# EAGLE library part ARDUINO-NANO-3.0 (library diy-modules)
Arduino Nano 3.0 and compatible devices More details available here: https://www.arduino.cc/en/Main/ArduinoBoardNano Click here to find device on ebay.com

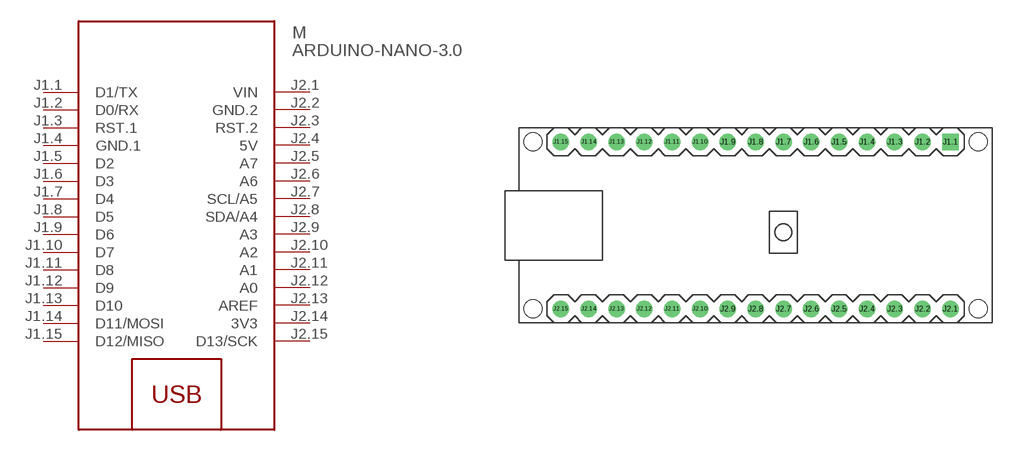
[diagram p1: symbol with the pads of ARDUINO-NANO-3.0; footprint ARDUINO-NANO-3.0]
Designator prefix M

## ARDUINO-NANO-3.0  [ARDUINO-NANO-3.0]
J1.1  D1/TX
J1.2  D0/RX
J1.3  RST.1
J1.4  GND.1  pwr
J1.5  D2
J1.6  D3
J1.7  D4
J1.8  D5
J1.9  D6
J1.10  D7
J1.11  D8
J1.12  D9
J1.13  D10
J1.14  D11/MOSI
J1.15  D12/MISO
J2.1  VIN  pwr
J2.2  GND.2  pwr
J2.3  RST.2
J2.4  5V  pwr
J2.5  A7
J2.6  A6
J2.7  SCL/A5
J2.8  SDA/A4
J2.9  A3
J2.10  A2
J2.11  A1
J2.12  A0
J2.13  AREF
J2.14  3V3  pwr
J2.15  D13/SCK

## Footprint ARDUINO-NANO-3.0 (pad centres in mm)
Arduino Nano 3.0
drill 1 square: J1.1 17.78,7.62
drill 1: J1.2 15.24,7.62; J1.3 12.7,7.62; J1.4 10.16,7.62; J1.5 7.62,7.62; J1.6 5.08,7.62; J1.7 2.54,7.62; J1.8 0,7.62; J1.9 -2.54,7.62; J1.10 -5.08,7.62; J1.11 -7.62,7.62; J1.12 -10.16,7.62; J1.13 -12.7,7.62; J1.14 -15.24,7.62; J1.15 -17.78,7.62; J2.1 17.78,-7.62; J2.2 15.24,-7.62; J2.3 12.7,-7.62; J2.4 10.16,-7.62; J2.5 7.62,-7.62; J2.6 5.08,-7.62; J2.7 2.54,-7.62; J2.8 0,-7.62; J2.9 -2.54,-7.62; J2.10 -5.08,-7.62; J2.11 -7.62,-7.62; J2.12 -10.16,-7.62; J2.13 -12.7,-7.62; J2.14 -15.24,-7.62; J2.15 -17.78,-7.62
hole 1.651 at -20.32,7.62
hole 1.651 at -20.32,-7.62
hole 1.651 at 20.32,-7.62
hole 1.651 at 20.32,7.62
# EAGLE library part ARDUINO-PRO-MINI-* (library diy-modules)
Arduino Pro Mini and compatible devices More details available here: https://www.arduino.cc/en/Main/ArduinoBoardProMini Click here to find device on ebay.com

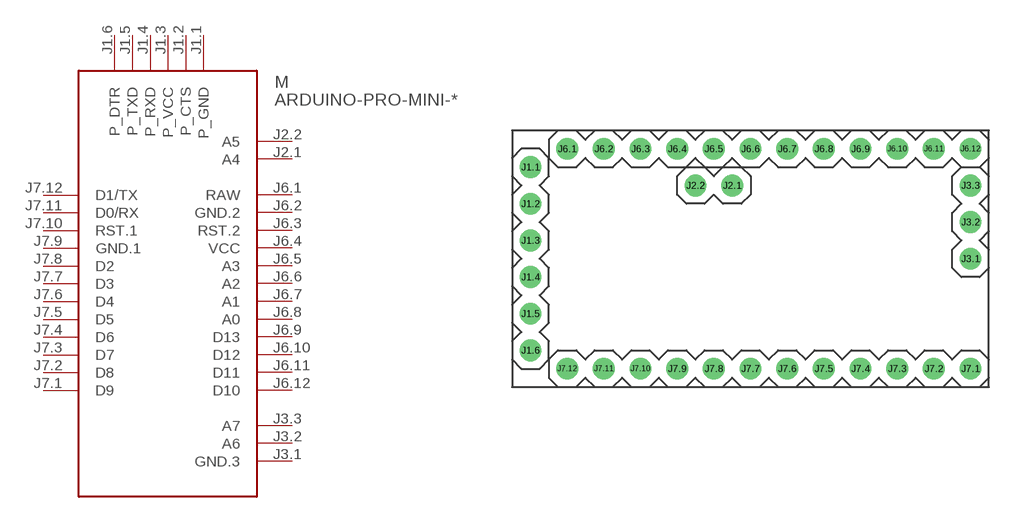
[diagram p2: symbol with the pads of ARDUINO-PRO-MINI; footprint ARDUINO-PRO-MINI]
Designator prefix M

## ARDUINO-PRO-MINI-3.3V, ARDUINO-PRO-MINI-5.0V  [ARDUINO-PRO-MINI]
J1.1  P_GND
J1.2  P_CTS
J1.3  P_VCC
J1.4  P_RXD
J1.5  P_TXD
J1.6  P_DTR
J2.1  A4
J2.2  A5
J3.1  GND.3
J3.2  A6
J3.3  A7
J6.1  RAW  pwr
J6.2  GND.2  pwr
J6.3  RST.2
J6.4  VCC  pwr
J6.5  A3
J6.6  A2
J6.7  A1
J6.8  A0
J6.9  D13
J6.10  D12
J6.11  D11
J6.12  D10
J7.1  D9
J7.2  D8
J7.3  D7
J7.4  D6
J7.5  D5
J7.6  D4
J7.7  D3
J7.8  D2
J7.9  GND.1  pwr
J7.10  RST.1
J7.11  D0/RX
J7.12  D1/TX

## Footprint ARDUINO-PRO-MINI (pad centres in mm)
Arduino Pro Mini
drill 1: J1.1 -15.24,6.35; J1.2 -15.24,3.81; J1.3 -15.24,1.27; J1.4 -15.24,-1.27; J1.5 -15.24,-3.81; J1.6 -15.24,-6.35; J2.1 -1.27,5.08; J2.2 -3.81,5.08; J3.1 15.24,0; J3.2 15.24,2.54; J3.3 15.24,5.08; J6.1 -12.7,7.62; J6.2 -10.16,7.62; J6.3 -7.62,7.62; J6.4 -5.08,7.62; J6.5 -2.54,7.62; J6.6 0,7.62; J6.7 2.54,7.62; J6.8 5.08,7.62; J6.9 7.62,7.62; J6.10 10.16,7.62; J6.11 12.7,7.62; J6.12 15.24,7.62; J7.1 15.24,-7.62; J7.2 12.7,-7.62; J7.3 10.16,-7.62; J7.4 7.62,-7.62; J7.5 5.08,-7.62; J7.6 2.54,-7.62; J7.7 0,-7.62; J7.8 -2.54,-7.62; J7.9 -5.08,-7.62; J7.10 -7.62,-7.62; J7.11 -10.16,-7.62; J7.12 -12.7,-7.62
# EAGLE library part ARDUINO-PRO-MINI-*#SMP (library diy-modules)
Arduino Pro Mini (and compatible devices) with 2 connectors only More details available here: https://www.arduino.cc/en/Main/ArduinoBoardProMini Click here to find device on ebay.com

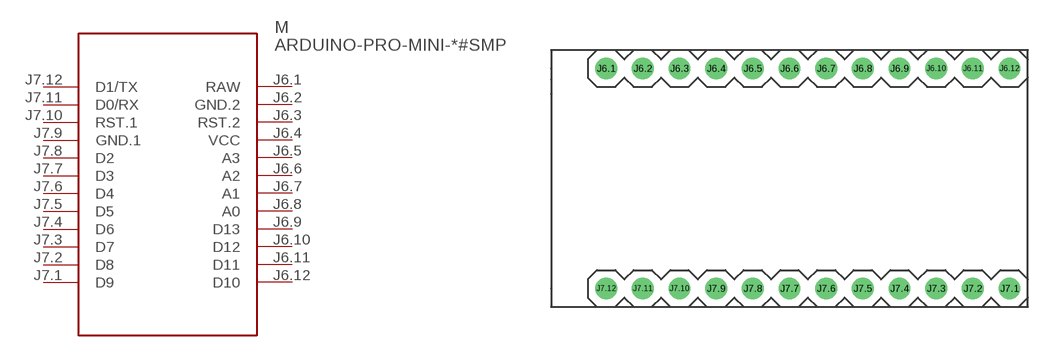
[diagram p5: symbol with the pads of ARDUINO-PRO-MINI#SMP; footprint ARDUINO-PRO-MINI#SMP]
Designator prefix M

## ARDUINO-PRO-MINI-3.3V#SMP, ARDUINO-PRO-MINI-5.0V#SMP  [ARDUINO-PRO-MINI#SMP]
J6.1  RAW  pwr
J6.2  GND.2  pwr
J6.3  RST.2
J6.4  VCC  pwr
J6.5  A3
J6.6  A2
J6.7  A1
J6.8  A0
J6.9  D13
J6.10  D12
J6.11  D11
J6.12  D10
J7.1  D9
J7.2  D8
J7.3  D7
J7.4  D6
J7.5  D5
J7.6  D4
J7.7  D3
J7.8  D2
J7.9  GND.1  pwr
J7.10  RST.1
J7.11  D0/RX
J7.12  D1/TX

## Footprint ARDUINO-PRO-MINI#SMP (pad centres in mm)
Arduino Pro Mini Footprint with 2 connectors only
drill 1: J6.1 -12.7,7.62; J6.2 -10.16,7.62; J6.3 -7.62,7.62; J6.4 -5.08,7.62; J6.5 -2.54,7.62; J6.6 0,7.62; J6.7 2.54,7.62; J6.8 5.08,7.62; J6.9 7.62,7.62; J6.10 10.16,7.62; J6.11 12.7,7.62; J6.12 15.24,7.62; J7.1 15.24,-7.62; J7.2 12.7,-7.62; J7.3 10.16,-7.62; J7.4 7.62,-7.62; J7.5 5.08,-7.62; J7.6 2.54,-7.62; J7.7 0,-7.62; J7.8 -2.54,-7.62; J7.9 -5.08,-7.62; J7.10 -7.62,-7.62; J7.11 -10.16,-7.62; J7.12 -12.7,-7.62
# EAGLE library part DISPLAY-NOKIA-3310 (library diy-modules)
84x48 Dot Matrix LCD Module based on Nokia 3310 display More details available here: https://arduinoandsoftware.wordpress.com/2012/12/30/nokia-33105110-3-3v-display-with-5v-arduino/

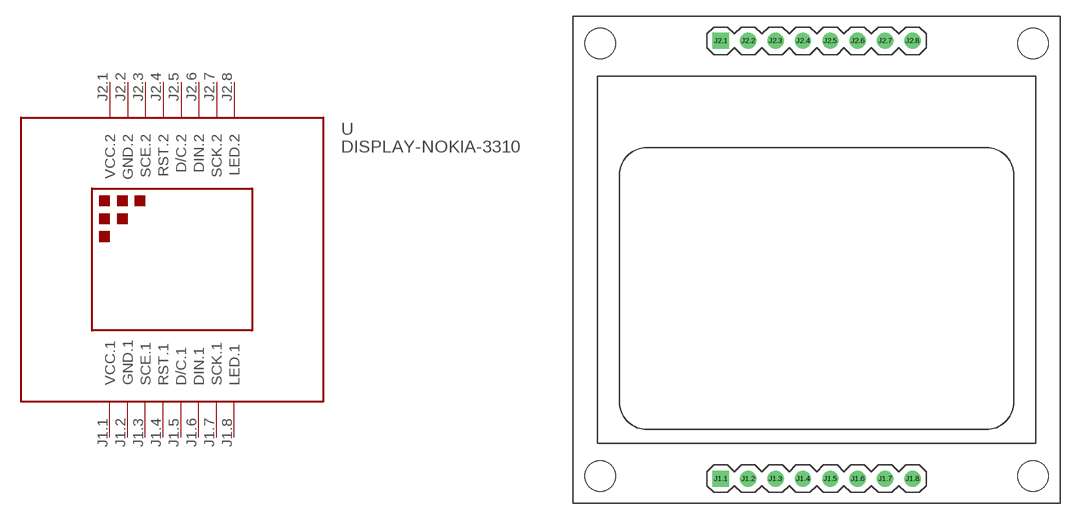
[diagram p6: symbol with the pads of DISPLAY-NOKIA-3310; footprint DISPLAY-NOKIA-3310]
Designator prefix -

## DISPLAY-NOKIA-3310  [DISPLAY-NOKIA-3310]
J1.1  VCC.1  pwr
J1.2  GND.1  pwr
J1.3  SCE.1
J1.4  RST.1
J1.5  D/C.1
J1.6  DIN.1
J1.7  SCK.1
J1.8  LED.1  in
J2.1  VCC.2  pwr
J2.2  GND.2  pwr
J2.3  SCE.2
J2.4  RST.2
J2.5  D/C.2
J2.6  DIN.2
J2.7  SCK.2
J2.8  LED.2  in

## Footprint DISPLAY-NOKIA-3310 (pad centres in mm)
84x48 Dot Matrix LCD Module based on Nokia 3310 display
drill 1 square: J1.1 -8.89,-20.32; J2.1 -8.89,20.32
drill 1: J1.2 -6.35,-20.32; J1.3 -3.81,-20.32; J1.4 -1.27,-20.32; J1.5 1.27,-20.32; J1.6 3.81,-20.32; J1.7 6.35,-20.32; J1.8 8.89,-20.32; J2.2 -6.35,20.32; J2.3 -3.81,20.32; J2.4 -1.27,20.32; J2.5 1.27,20.32; J2.6 3.81,20.32; J2.7 6.35,20.32; J2.8 8.89,20.32
hole 2.8 at -20.066,-20.066
hole 2.8 at 20.066,-20.066
hole 2.8 at 20.066,20.066
hole 2.8 at -20.066,20.066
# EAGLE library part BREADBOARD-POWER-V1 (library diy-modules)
Breadboard Power Adapter with onboard 3.3V and 5V regulators

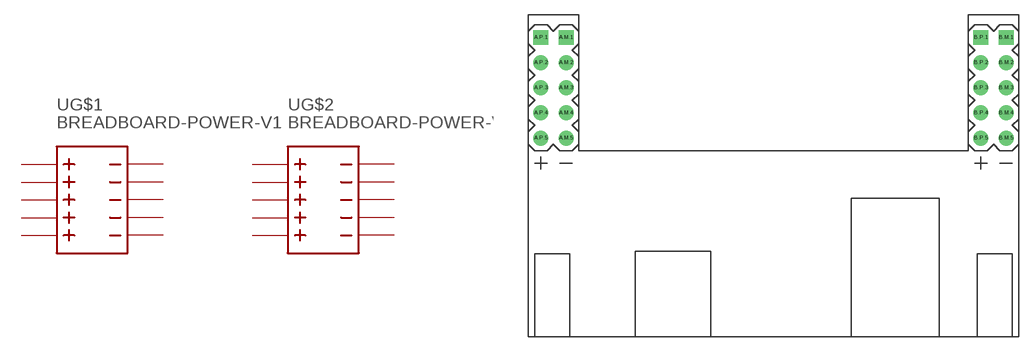
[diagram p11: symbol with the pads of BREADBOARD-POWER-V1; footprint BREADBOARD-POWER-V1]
Designator prefix -; gates G$1=BREADBOARD-POWER-V1 G$2=BREADBOARD-POWER-V1

## BREADBOARD-POWER-V1  [BREADBOARD-POWER-V1]
A.M.1  G$1:M.1
A.M.2  G$1:M.2
A.M.3  G$1:M.3
A.M.4  G$1:M.4
A.M.5  G$1:M.5
A.P.1  G$1:P.1
A.P.2  G$1:P.2
A.P.3  G$1:P.3
A.P.4  G$1:P.4
A.P.5  G$1:P.5
B.M.1  G$2:M.1
B.M.2  G$2:M.2
B.M.3  G$2:M.3
B.M.4  G$2:M.4
B.M.5  G$2:M.5
B.P.1  G$2:P.1
B.P.2  G$2:P.2
B.P.3  G$2:P.3
B.P.4  G$2:P.4
B.P.5  G$2:P.5

## Footprint BREADBOARD-POWER-V1 (pad centres in mm)
Breadboard Power Adapter with onboard 3.3V and 5V regulators
drill 1 square: A.M.1 -20.955,13.97; A.P.1 -23.495,13.97; B.M.1 23.495,13.97; B.P.1 20.955,13.97
drill 1: A.M.2 -20.955,11.43; A.M.3 -20.955,8.89; A.M.4 -20.955,6.35; A.M.5 -20.955,3.81; A.P.2 -23.495,11.43; A.P.3 -23.495,8.89; A.P.4 -23.495,6.35; A.P.5 -23.495,3.81; B.M.2 23.495,11.43; B.M.3 23.495,8.89; B.M.4 23.495,6.35; B.M.5 23.495,3.81; B.P.2 20.955,11.43; B.P.3 20.955,8.89; B.P.4 20.955,6.35; B.P.5 20.955,3.81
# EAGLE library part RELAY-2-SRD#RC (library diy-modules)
2-Channel Relay Module based on SRD-05VDC-SL-C relays Symbol with relays pins Click here to find device on ebay.com

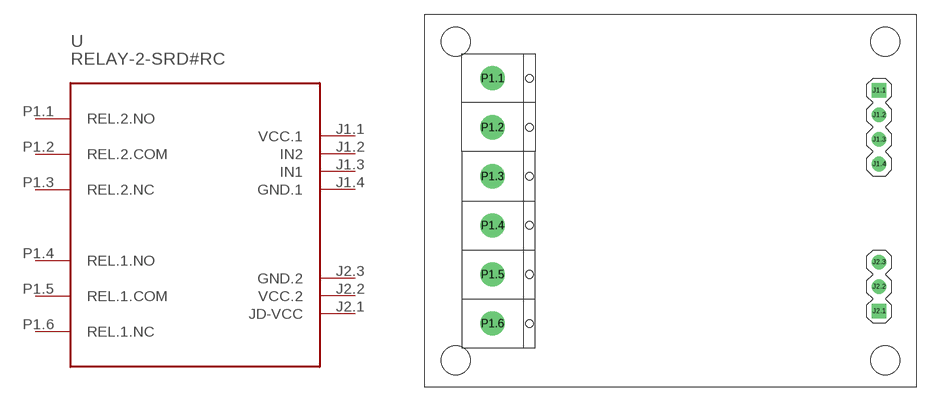
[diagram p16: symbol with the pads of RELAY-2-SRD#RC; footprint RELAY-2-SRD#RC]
Designator prefix -

## RELAY-2-SRD#RC  [RELAY-2-SRD#RC]
J1.1  VCC.1  pwr
J1.2  IN2
J1.3  IN1
J1.4  GND.1  pwr
J2.1  JD-VCC
J2.2  VCC.2  pwr
J2.3  GND.2  pwr
P1.1  REL.2.NO
P1.2  REL.2.COM
P1.3  REL.2.NC
P1.4  REL.1.NO
P1.5  REL.1.COM
P1.6  REL.1.NC

## Footprint RELAY-2-SRD#RC (pad centres in mm)
2-Channel Relay Module based on SRD-05VDC-SL-C relays Footprint with relays connector
drill 1 square: J1.1 21.59,11.43; J2.1 21.59,-11.43
drill 1: J1.2 21.59,8.89; J1.3 21.59,6.35; J1.4 21.59,3.81; J2.2 21.59,-8.89; J2.3 21.59,-6.35
drill 1.2 pad 2.5: P1.1 -18.415,12.7; P1.2 -18.415,7.62; P1.3 -18.415,2.54; P1.4 -18.415,-2.54; P1.5 -18.415,-7.62; P1.6 -18.415,-12.7
hole 3 at -22.225,16.51
hole 3 at 22.225,16.51
hole 3 at 22.225,-16.51
hole 3 at -22.225,-16.51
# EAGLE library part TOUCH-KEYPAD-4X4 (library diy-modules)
16 Channel Capacitive Touch Keypad Click here to find device on ebay.com

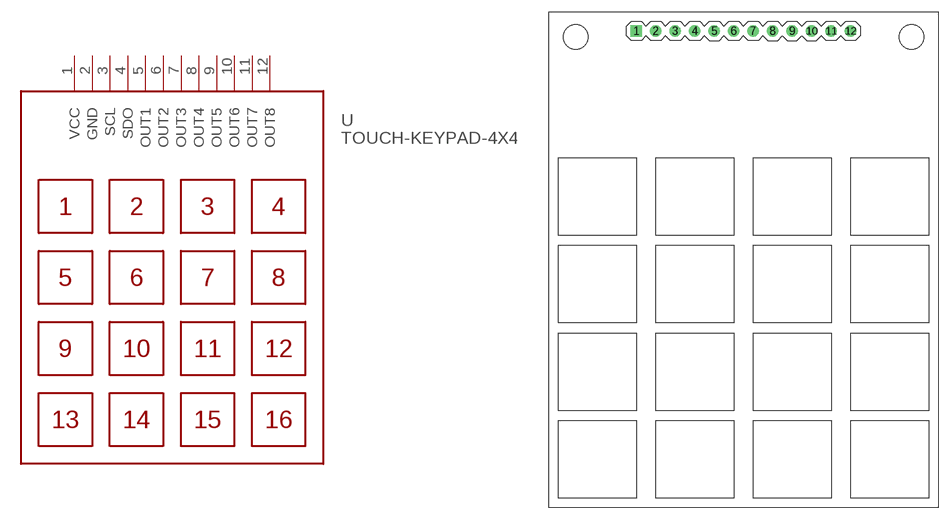
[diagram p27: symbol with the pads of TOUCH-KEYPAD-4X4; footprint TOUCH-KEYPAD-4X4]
Designator prefix -

## TOUCH-KEYPAD-4X4  [TOUCH-KEYPAD-4X4]
1  VCC  pwr
2  GND  pwr
3  SCL
4  SDO
5  OUT1
6  OUT2
7  OUT3
8  OUT4
9  OUT5
10  OUT6
11  OUT7
12  OUT8

## Footprint TOUCH-KEYPAD-4X4 (pad centres in mm)
16 Channel Capacitive Touch Keypad
drill 1 square: 1 -13.97,30.48
drill 1: 2 -11.43,30.48; 3 -8.89,30.48; 4 -6.35,30.48; 5 -3.81,30.48; 6 -1.27,30.48; 7 1.27,30.48; 8 3.81,30.48; 9 6.35,30.48; 10 8.89,30.48; 11 11.43,30.48; 12 13.97,30.48
hole 3.2 at -21.907,29.718
hole 3.2 at 21.907,29.718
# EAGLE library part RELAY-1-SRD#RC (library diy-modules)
1-Channel Relay Module based on SRD-05VDC-SL-C relays Symbol with relays pins Click here to find device on ebay.com

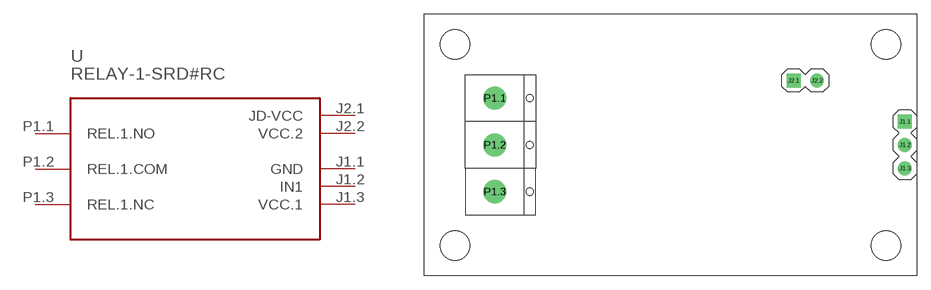
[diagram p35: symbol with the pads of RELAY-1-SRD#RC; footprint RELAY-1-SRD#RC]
Designator prefix -

## RELAY-1-SRD#RC  [RELAY-1-SRD#RC]
J1.1  GND  pwr
J1.2  IN1
J1.3  VCC.1  pwr
J2.1  JD-VCC
J2.2  VCC.2  pwr
P1.1  REL.1.NO
P1.2  REL.1.COM
P1.3  REL.1.NC

## Footprint RELAY-1-SRD#RC (pad centres in mm)
1-Channel Relay Module based on SRD-05VDC-SL-C relay Footprint with relays connector
drill 1 square: J1.1 25.4,2.54; J2.1 13.335,6.985
drill 1: J1.2 25.4,0; J1.3 25.4,-2.54; J2.2 15.875,6.985
drill 1.2 pad 2.5: P1.1 -19.05,5.08; P1.2 -19.05,0; P1.3 -19.05,-5.08
hole 3.2 at -23.368,10.922
hole 3.2 at 23.368,10.922
hole 3.2 at 23.368,-10.922
hole 3.2 at -23.368,-10.922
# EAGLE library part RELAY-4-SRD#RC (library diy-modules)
4-Channel Relay Module based on SRD-05VDC-SL-C relays Symbol with relays pins Click here to find device on ebay.com

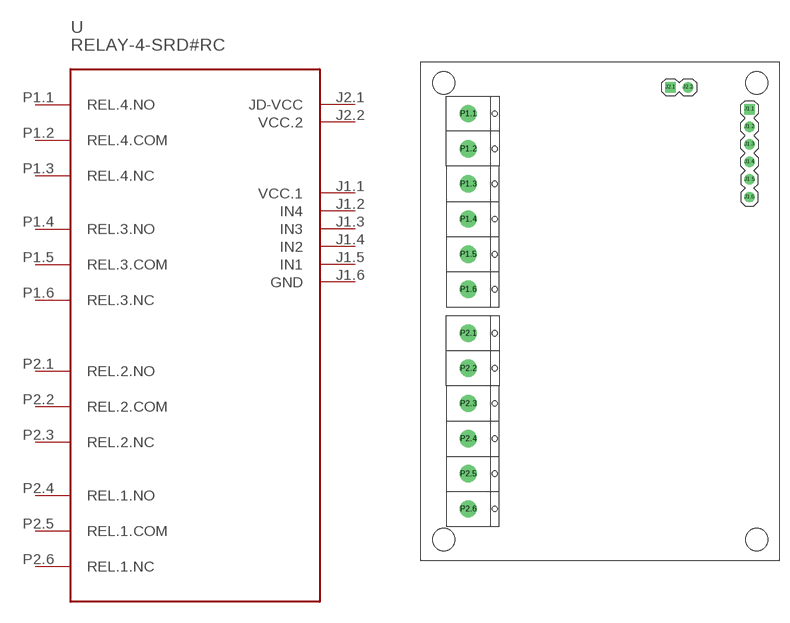
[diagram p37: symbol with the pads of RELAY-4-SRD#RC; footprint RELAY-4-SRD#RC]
Designator prefix -

## RELAY-4-SRD#RC  [RELAY-4-SRD#RC]
J1.1  VCC.1  pwr
J1.2  IN4
J1.3  IN3
J1.4  IN2
J1.5  IN1
J1.6  GND  pwr
J2.1  JD-VCC
J2.2  VCC.2  pwr
P1.1  REL.4.NO
P1.2  REL.4.COM
P1.3  REL.4.NC
P1.4  REL.3.NO
P1.5  REL.3.COM
P1.6  REL.3.NC
P2.1  REL.2.NO
P2.2  REL.2.COM
P2.3  REL.2.NC
P2.4  REL.1.NO
P2.5  REL.1.COM
P2.6  REL.1.NC

## Footprint RELAY-4-SRD#RC (pad centres in mm)
4-Channel Relay Module based on SRD-05VDC-SL-C relays Footprint with relays connector
drill 1 square: J1.1 20.32,29.21; J2.1 8.89,32.385
drill 1: J1.2 20.32,26.67; J1.3 20.32,24.13; J1.4 20.32,21.59; J1.5 20.32,19.05; J1.6 20.32,16.51; J2.2 11.43,32.385
drill 1.2 pad 2.5: P1.1 -20.32,28.575; P1.2 -20.32,23.495; P1.3 -20.32,18.415; P1.4 -20.32,13.335; P1.5 -20.32,8.255; P1.6 -20.32,3.175; P2.1 -20.32,-3.175; P2.2 -20.32,-8.255; P2.3 -20.32,-13.335; P2.4 -20.32,-18.415; P2.5 -20.32,-23.495; P2.6 -20.32,-28.575
hole 3.2 at -23.876,33.02
hole 3.2 at 21.336,33.02
hole 3.2 at 21.336,-33.02
hole 3.2 at -23.876,-33.02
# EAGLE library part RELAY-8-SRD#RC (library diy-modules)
8-Channel Relay Module based on SRD-05VDC-SL-C relays Symbol with relays pins Click here to find device on ebay.com

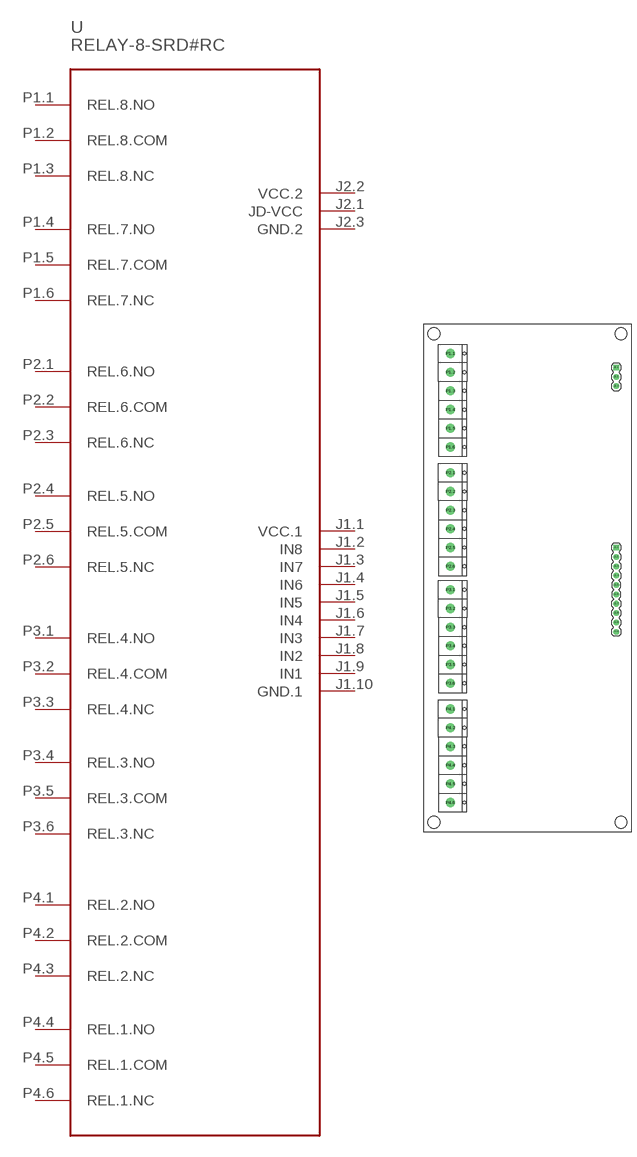
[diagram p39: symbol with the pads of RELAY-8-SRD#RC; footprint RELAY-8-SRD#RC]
Designator prefix -

## RELAY-8-SRD#RC  [RELAY-8-SRD#RC]
J1.1  VCC.1  pwr
J1.2  IN8
J1.3  IN7
J1.4  IN6
J1.5  IN5
J1.6  IN4
J1.7  IN3
J1.8  IN2
J1.9  IN1
J1.10  GND.1  pwr
J2.1  JD-VCC
J2.2  VCC.2  pwr
J2.3  GND.2  pwr
P1.1  REL.8.NO
P1.2  REL.8.COM
P1.3  REL.8.NC
P1.4  REL.7.NO
P1.5  REL.7.COM
P1.6  REL.7.NC
P2.1  REL.6.NO
P2.2  REL.6.COM
P2.3  REL.6.NC
P2.4  REL.5.NO
P2.5  REL.5.COM
P2.6  REL.5.NC
P3.1  REL.4.NO
P3.2  REL.4.COM
P3.3  REL.4.NC
P3.4  REL.3.NO
P3.5  REL.3.COM
P3.6  REL.3.NC
P4.1  REL.2.NO
P4.2  REL.2.COM
P4.3  REL.2.NC
P4.4  REL.1.NO
P4.5  REL.1.COM
P4.6  REL.1.NC

## Footprint RELAY-8-SRD#RC (pad centres in mm)
8-Channel Relay Module based on SRD-05VDC-SL-C relays Footprint with relays connector
drill 1 square: J1.1 24.13,8.255; J2.1 24.13,57.15
drill 1: J1.2 24.13,5.715; J1.3 24.13,3.175; J1.4 24.13,0.635; J1.5 24.13,-1.905; J1.6 24.13,-4.445; J1.7 24.13,-6.985; J1.8 24.13,-9.525; J1.9 24.13,-12.065; J1.10 24.13,-14.605; J2.2 24.13,54.61; J2.3 24.13,52.07
drill 1.2 pad 2.5: P1.1 -20.955,60.96; P1.2 -20.955,55.88; P1.3 -20.955,50.8; P1.4 -20.955,45.72; P1.5 -20.955,40.64; P1.6 -20.955,35.56; P2.1 -20.955,28.575; P2.2 -20.955,23.495; P2.3 -20.955,18.415; P2.4 -20.955,13.335; P2.5 -20.955,8.255; P2.6 -20.955,3.175; P3.1 -20.955,-3.175; P3.2 -20.955,-8.255; P3.3 -20.955,-13.335; P3.4 -20.955,-18.415; P3.5 -20.955,-23.495; P3.6 -20.955,-28.575; P4.1 -20.955,-35.56; P4.2 -20.955,-40.64; P4.3 -20.955,-45.72; P4.4 -20.955,-50.8; P4.5 -20.955,-55.88; P4.6 -20.955,-60.96
hole 3.2 at -25.4,66.294
hole 3.2 at 25.4,66.294
hole 3.2 at 25.4,-66.294
hole 3.2 at -25.4,-66.294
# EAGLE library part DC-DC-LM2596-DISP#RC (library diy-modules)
DC/DC Step-Down Regulator with Voltage Display based on LM2596-ADJ chip Symbol with input and output connectors More details available here: http://www.instructables.com/id/The-Introduction-of-LM2596-Step-Down-Power-Module-/ LM2596 datasheet available here: http://www.ti.com/lit/ds/symlink/lm2596.pdf Click here to find device on ebay.com

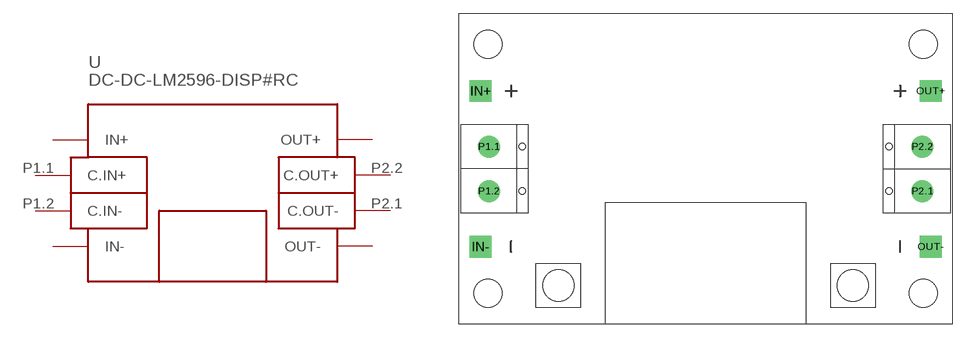
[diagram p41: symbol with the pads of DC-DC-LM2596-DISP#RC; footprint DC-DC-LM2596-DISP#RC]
Designator prefix -

## DC-DC-LM2596-DISP#RC  [DC-DC-LM2596-DISP#RC]
IN+  IN+
IN-  IN-
OUT+  OUT+
OUT-  OUT-
P1.1  C.IN+
P1.2  C.IN-
P2.1  C.OUT-
P2.2  C.OUT+

## Footprint DC-DC-LM2596-DISP#RC (pad centres in mm)
DC/DC Step-Down Regulator with Voltage Display based on LM2596-ADJ chip Footprint with connector pins.
drill 1.5 pad 2.5 square: IN+ -25.718,8.89; IN- -25.718,-8.89; OUT+ 25.718,8.89; OUT- 25.718,-8.89
drill 1.2 pad 2.5: P1.1 -24.765,2.54; P1.2 -24.765,-2.54; P2.1 24.765,-2.54; P2.2 24.765,2.54
hole 3.2 at -24.892,14.224
hole 3.2 at 24.892,-14.224
hole 3.2 at 24.892,14.224
hole 3.2 at -24.892,-14.224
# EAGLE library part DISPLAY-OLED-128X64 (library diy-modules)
128x64 Dot Matrix OLED Module based on SSD1306 chip Variant with SPI interface More details available here: http://www.instructables.com/id/How-to-use-OLED-display-arduino-module/ SSD1306 datasheet: https://cdn-shop.adafruit.com/datasheets/SSD1306.pdf Click here to find device on ebay.com Note: There are two variants: I2C and SPI. Search for the proper version.

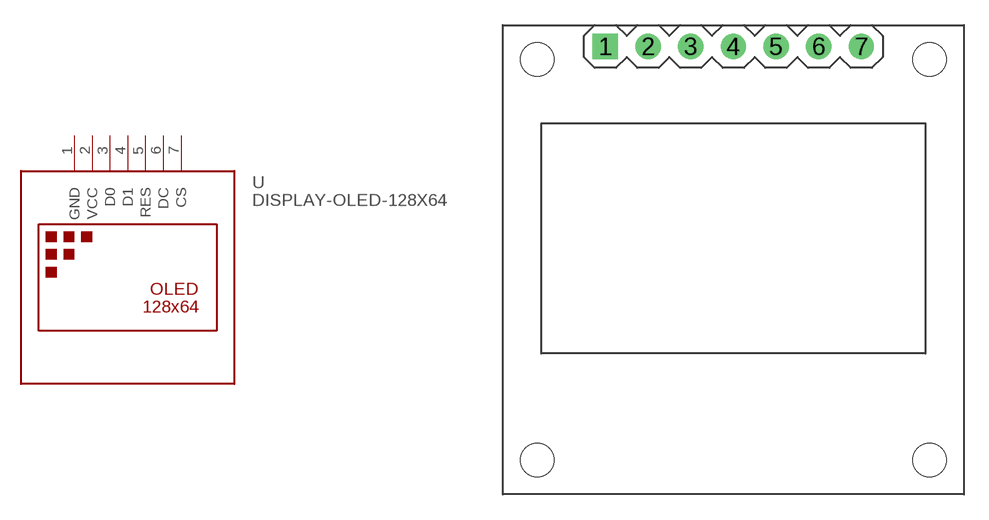
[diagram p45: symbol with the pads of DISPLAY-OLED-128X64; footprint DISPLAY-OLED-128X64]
Designator prefix -

## DISPLAY-OLED-128X64  [DISPLAY-OLED-128X64]
1  GND  pwr
2  VCC  pwr
3  D0
4  D1
5  RES
6  DC
7  CS

## Footprint DISPLAY-OLED-128X64 (pad centres in mm)
128x64 Dot Matrix OLED Module Variant with SPI interface
drill 1 square: 1 -7.62,12.7
drill 1: 2 -5.08,12.7; 3 -2.54,12.7; 4 0,12.7; 5 2.54,12.7; 6 5.08,12.7; 7 7.62,12.7
hole 2 at -11.684,11.938
hole 2 at 11.684,11.938
hole 2 at 11.684,-11.938
hole 2 at -11.684,-11.938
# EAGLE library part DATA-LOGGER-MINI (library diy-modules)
Mini Data Logger with microSD card and battery powered RTC based on DS1307 chip Arduino library for DS1307 and description are available here: https://www.pjrc.com/teensy/td_libs_DS1307RTC.html Tutorial how to use SD card with Arduino: https://www.arduino.cc/en/reference/SD Click here to find device on ebay.com

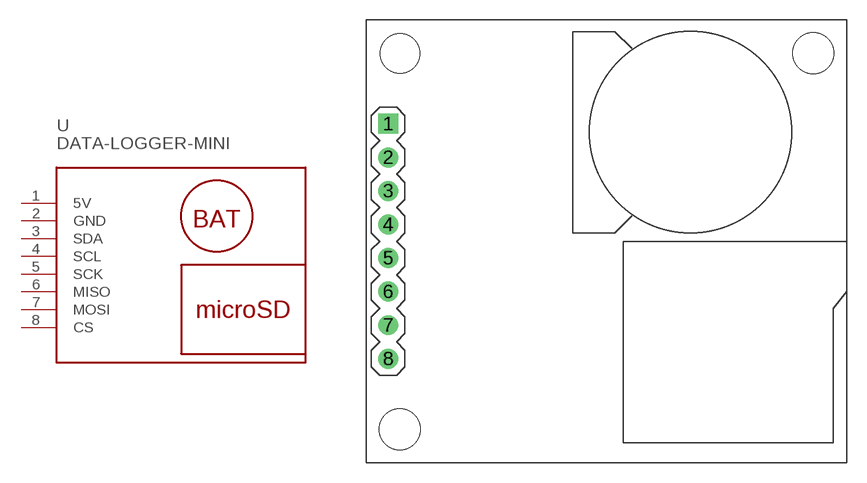
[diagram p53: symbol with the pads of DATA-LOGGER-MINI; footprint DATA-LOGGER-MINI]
Designator prefix -

## DATA-LOGGER-MINI  [DATA-LOGGER-MINI]
1  5V  pwr
2  GND  pwr
3  SDA
4  SCL
5  SCK
6  MISO
7  MOSI
8  CS  pwr

## Footprint DATA-LOGGER-MINI (pad centres in mm)
Mini Data Logger with microSD card and battery powered RTC based on DS1307 chip
drill 1 square: 1 -16.51,8.89
drill 1: 2 -16.51,6.35; 3 -16.51,3.81; 4 -16.51,1.27; 5 -16.51,-1.27; 6 -16.51,-3.81; 7 -16.51,-6.35; 8 -16.51,-8.89
hole 3 at -15.621,14.224
hole 3.1 at -15.621,-14.224
hole 3.1 at 15.621,14.224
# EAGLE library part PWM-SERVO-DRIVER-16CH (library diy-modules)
16-Channel 12-bit PWM/Servo Driver based on PCA9685 chip PCA9685 datasheet is available here: http://www.nxp.com/documents/data_sheet/PCA9685.pdf Arduino Library for PCA9685 is available here: https://github.com/kasperskaarhoj/PCA9685-Arduino-Library Click here to find device on ebay.com

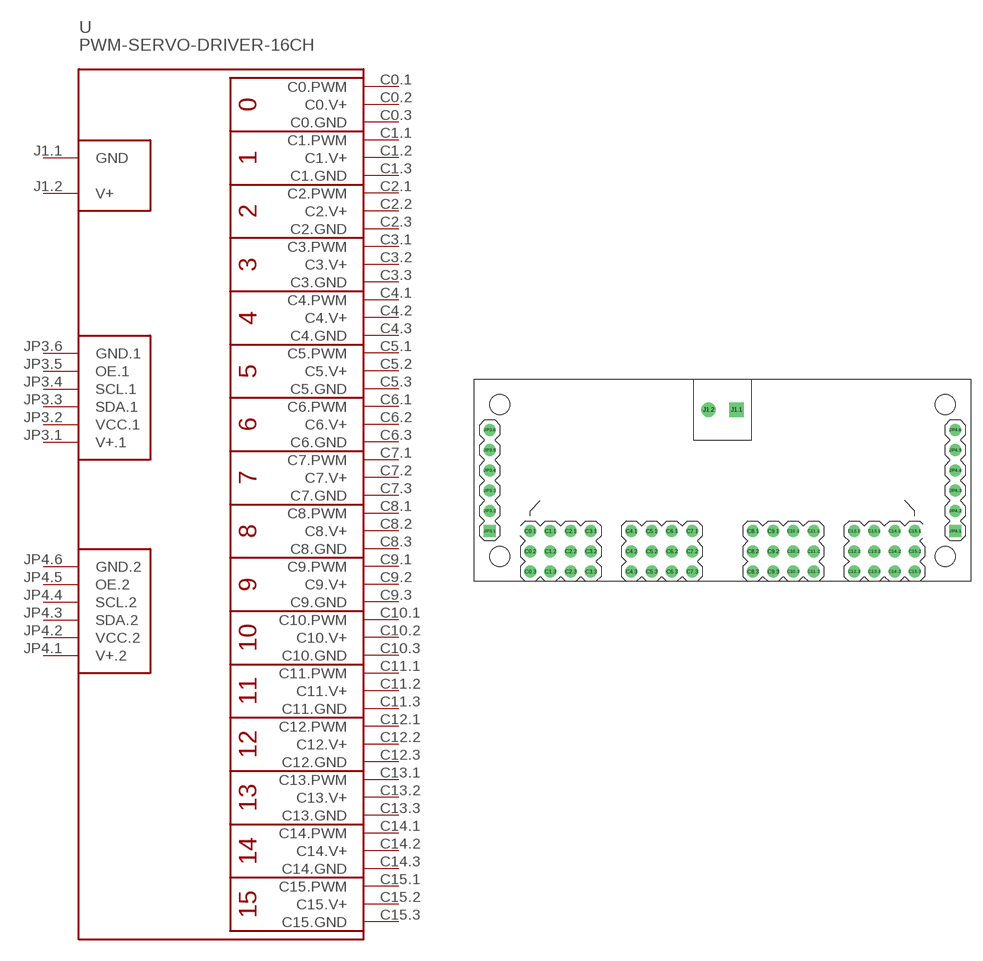
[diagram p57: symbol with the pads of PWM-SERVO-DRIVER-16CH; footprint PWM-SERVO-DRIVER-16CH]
Designator prefix -

## PWM-SERVO-DRIVER-16CH  [PWM-SERVO-DRIVER-16CH]
C0.1  C0.PWM
C0.2  C0.V+
C0.3  C0.GND
C1.1  C1.PWM
C1.2  C1.V+
C1.3  C1.GND
C2.1  C2.PWM
C2.2  C2.V+
C2.3  C2.GND
C3.1  C3.PWM
C3.2  C3.V+
C3.3  C3.GND
C4.1  C4.PWM
C4.2  C4.V+
C4.3  C4.GND
C5.1  C5.PWM
C5.2  C5.V+
C5.3  C5.GND
C6.1  C6.PWM
C6.2  C6.V+
C6.3  C6.GND
C7.1  C7.PWM
C7.2  C7.V+
C7.3  C7.GND
C8.1  C8.PWM
C8.2  C8.V+
C8.3  C8.GND
C9.1  C9.PWM
C9.2  C9.V+
C9.3  C9.GND
C10.1  C10.PWM
C10.2  C10.V+
C10.3  C10.GND
C11.1  C11.PWM
C11.2  C11.V+
C11.3  C11.GND
C12.1  C12.PWM
C12.2  C12.V+
C12.3  C12.GND
C13.1  C13.PWM
C13.2  C13.V+
C13.3  C13.GND
C14.1  C14.PWM
C14.2  C14.V+
C14.3  C14.GND
C15.1  C15.PWM
C15.2  C15.V+
C15.3  C15.GND
J1.1  GND  pwr
J1.2  V+  pwr
JP3.1  V+.1  pwr
JP3.2  VCC.1  pwr
JP3.3  SDA.1
JP3.4  SCL.1
JP3.5  OE.1
JP3.6  GND.1  pwr
JP4.1  V+.2  pwr
JP4.2  VCC.2  pwr
JP4.3  SDA.2
JP4.4  SCL.2
JP4.5  OE.2
JP4.6  GND.2  pwr

## Footprint PWM-SERVO-DRIVER-16CH (pad centres in mm)
16-Channel 12-bit PWM/Servo Driver based on PCA9685 chip
drill 1: C0.1 -24.13,-6.35; C0.2 -24.13,-8.89; C0.3 -24.13,-11.43; C1.1 -21.59,-6.35; C1.2 -21.59,-8.89; C1.3 -21.59,-11.43; C2.1 -19.05,-6.35; C2.2 -19.05,-8.89; C2.3 -19.05,-11.43; C3.1 -16.51,-6.35; C3.2 -16.51,-8.89; C3.3 -16.51,-11.43; C4.1 -11.43,-6.35; C4.2 -11.43,-8.89; C4.3 -11.43,-11.43; C5.1 -8.89,-6.35; C5.2 -8.89,-8.89; C5.3 -8.89,-11.43; C6.1 -6.35,-6.35; C6.2 -6.35,-8.89; C6.3 -6.35,-11.43; C7.1 -3.81,-6.35; C7.2 -3.81,-8.89; C7.3 -3.81,-11.43; C8.1 3.81,-6.35; C8.2 3.81,-8.89; C8.3 3.81,-11.43; C9.1 6.35,-6.35; C9.2 6.35,-8.89; C9.3 6.35,-11.43; C10.1 8.89,-6.35; C10.2 8.89,-8.89; C10.3 8.89,-11.43; C11.1 11.43,-6.35; C11.2 11.43,-8.89; C11.3 11.43,-11.43; C12.1 16.51,-6.35; C12.2 16.51,-8.89; C12.3 16.51,-11.43; C13.1 19.05,-6.35; C13.2 19.05,-8.89; C13.3 19.05,-11.43; C14.1 21.59,-6.35; C14.2 21.59,-8.89; C14.3 21.59,-11.43; C15.1 24.13,-6.35; C15.2 24.13,-8.89; C15.3 24.13,-11.43; JP3.2 -29.21,-3.81; JP3.3 -29.21,-1.27; JP3.4 -29.21,1.27; JP3.5 -29.21,3.81; JP3.6 -29.21,6.35; JP4.2 29.21,-3.81; JP4.3 29.21,-1.27; JP4.4 29.21,1.27; JP4.5 29.21,3.81; JP4.6 29.21,6.35
drill 1.2 square: J1.1 1.753,8.89
drill 1.2: J1.2 -1.753,8.89
drill 1 square: JP3.1 -29.21,-6.35; JP4.1 29.21,-6.35
hole 2.5 at -27.94,9.525
hole 2.5 at -27.94,-9.525
hole 2.5 at 27.94,9.525
hole 2.5 at 27.94,-9.525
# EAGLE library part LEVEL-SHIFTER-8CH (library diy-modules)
8-Channel Bi-Directional Logic Level Converter based on BSS128 transistors Click here to find device on ebay.com Note: There are many variants. Search for the proper version.

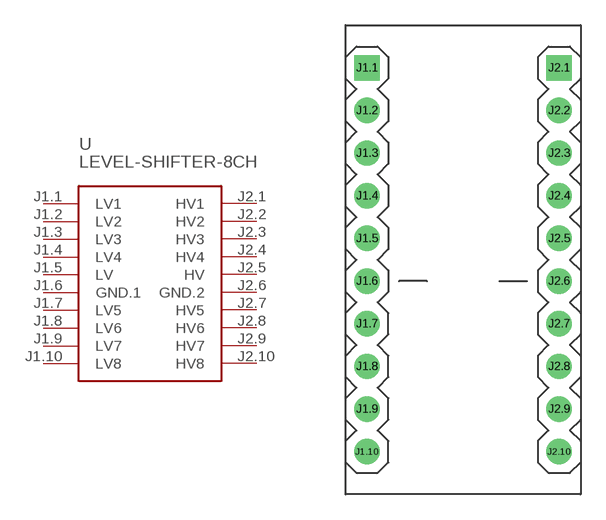
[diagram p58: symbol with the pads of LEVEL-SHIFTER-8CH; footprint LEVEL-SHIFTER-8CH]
Designator prefix -

## LEVEL-SHIFTER-8CH  [LEVEL-SHIFTER-8CH]
J1.1  LV1
J1.2  LV2
J1.3  LV3
J1.4  LV4
J1.5  LV  pwr
J1.6  GND.1  pwr
J1.7  LV5
J1.8  LV6
J1.9  LV7
J1.10  LV8
J2.1  HV1
J2.2  HV2
J2.3  HV3
J2.4  HV4
J2.5  HV  pwr
J2.6  GND.2  pwr
J2.7  HV5
J2.8  HV6
J2.9  HV7
J2.10  HV8

## Footprint LEVEL-SHIFTER-8CH (pad centres in mm)
8-Channel Bi-Directional Logic Level Converter based on BSS128 transistors
drill 1 square: J1.1 -5.715,11.43; J2.1 5.715,11.43
drill 1: J1.2 -5.715,8.89; J1.3 -5.715,6.35; J1.4 -5.715,3.81; J1.5 -5.715,1.27; J1.6 -5.715,-1.27; J1.7 -5.715,-3.81; J1.8 -5.715,-6.35; J1.9 -5.715,-8.89; J1.10 -5.715,-11.43; J2.2 5.715,8.89; J2.3 5.715,6.35; J2.4 5.715,3.81; J2.5 5.715,1.27; J2.6 5.715,-1.27; J2.7 5.715,-3.81; J2.8 5.715,-6.35; J2.9 5.715,-8.89; J2.10 5.715,-11.43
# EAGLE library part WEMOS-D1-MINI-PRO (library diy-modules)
WEMOS D1 mini Pro: Mini Wi-Fi Board based on ESP-8266EX chip More details can be found here: https://www.wemos.cc/product/d1-mini-pro.html Click here to find device on ebay.com

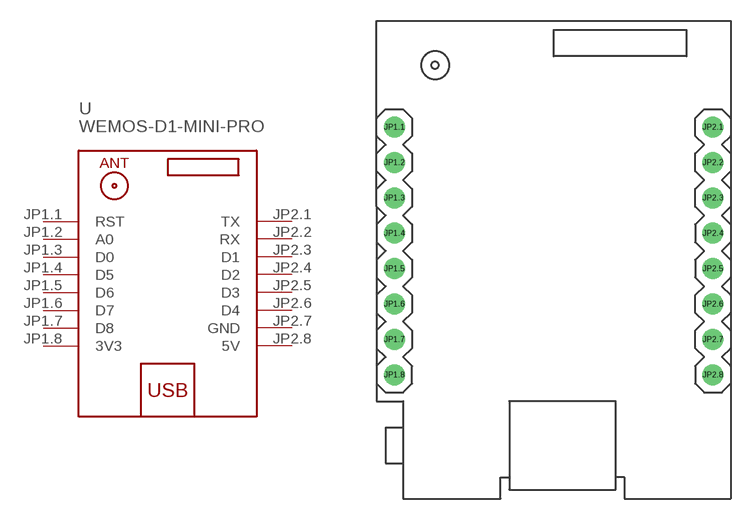
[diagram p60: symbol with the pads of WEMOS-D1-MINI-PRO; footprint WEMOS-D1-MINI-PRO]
Designator prefix -

## WEMOS-D1-MINI-PRO  [WEMOS-D1-MINI-PRO]
JP1.1  RST
JP1.2  A0
JP1.3  D0
JP1.4  D5
JP1.5  D6
JP1.6  D7
JP1.7  D8
JP1.8  3V3  pwr
JP2.1  TX
JP2.2  RX
JP2.3  D1
JP2.4  D2
JP2.5  D3
JP2.6  D4
JP2.7  GND  pwr
JP2.8  5V  pwr

## Footprint WEMOS-D1-MINI-PRO (pad centres in mm)
WEMOS D1 mini Pro: Mini Wi-Fi Board based on ESP-8266EX chip
drill 1: JP1.1 -11.43,9.525; JP1.2 -11.43,6.985; JP1.3 -11.43,4.445; JP1.4 -11.43,1.905; JP1.5 -11.43,-0.635; JP1.6 -11.43,-3.175; JP1.7 -11.43,-5.715; JP1.8 -11.43,-8.255; JP2.1 11.43,9.525; JP2.2 11.43,6.985; JP2.3 11.43,4.445; JP2.4 11.43,1.905; JP2.5 11.43,-0.635; JP2.6 11.43,-3.175; JP2.7 11.43,-5.715; JP2.8 11.43,-8.255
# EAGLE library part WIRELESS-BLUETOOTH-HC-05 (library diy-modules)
Bluetooth Transceiver Module based on HC-05 board Tutorial is available here: https://arduino-info.wikispaces.com/BlueTooth-HC05-HC06-Modules-How-To Click here to find device on ebay.com

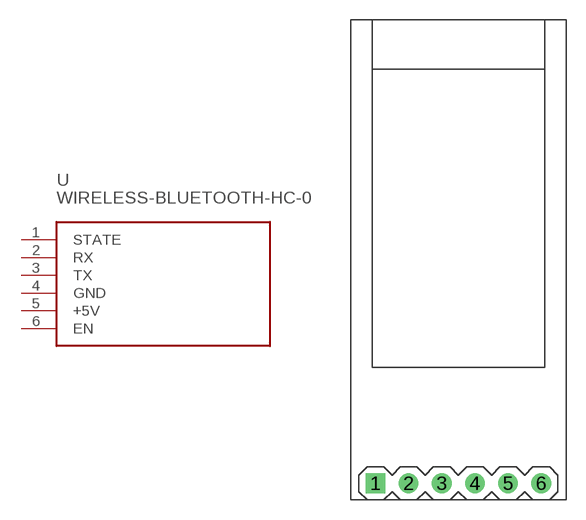
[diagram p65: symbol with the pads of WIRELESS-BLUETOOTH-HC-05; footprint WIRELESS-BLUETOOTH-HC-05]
Designator prefix -

## WIRELESS-BLUETOOTH-HC-05  [WIRELESS-BLUETOOTH-HC-05]
1  STATE
2  RX
3  TX
4  GND  pwr
5  +5V  pwr
6  EN

## Footprint WIRELESS-BLUETOOTH-HC-05 (pad centres in mm)
Bluetooth Transceiver Module based on HC-05 board
drill 1 square: 1 -6.35,-17.145
drill 1: 2 -3.81,-17.145; 3 -1.27,-17.145; 4 1.27,-17.145; 5 3.81,-17.145; 6 6.35,-17.145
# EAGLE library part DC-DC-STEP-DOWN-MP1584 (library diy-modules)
DC/DC Step-Down Regulator based on MP1584 chip MP1584 datasheet available here: http://www.haoyuelectronics.com/Attachment/MP1584/MP1584.pdf Click here to find device on ebay.com

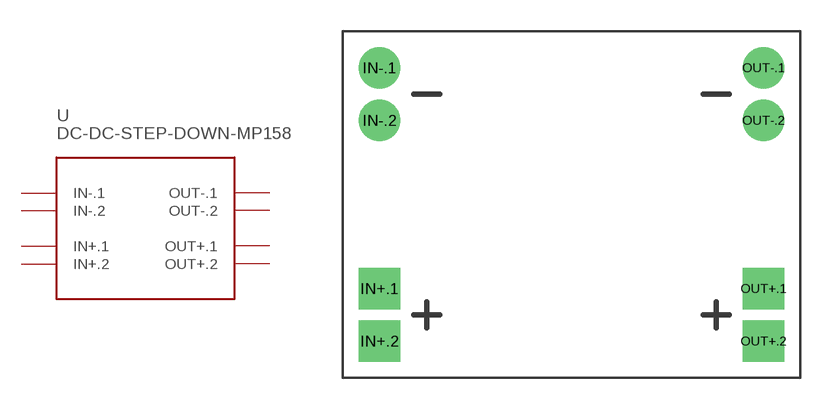
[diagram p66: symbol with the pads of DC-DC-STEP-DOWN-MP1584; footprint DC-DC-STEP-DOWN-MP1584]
Designator prefix -

## DC-DC-STEP-DOWN-MP1584  [DC-DC-STEP-DOWN-MP1584]
IN+.1  IN+.1
IN+.2  IN+.2
IN-.1  IN-.1
IN-.2  IN-.2
OUT+.1  OUT+.1
OUT+.2  OUT+.2
OUT-.1  OUT-.1
OUT-.2  OUT-.2

## Footprint DC-DC-STEP-DOWN-MP1584 (pad centres in mm)
DC/DC Step-Down Regulator based on MP1584 chip
drill 1.2 pad 2 square: IN+.1 -9.271,-4.064; IN+.2 -9.271,-6.604; OUT+.1 9.271,-4.064; OUT+.2 9.271,-6.604
drill 1.2 pad 2: IN-.1 -9.271,6.604; IN-.2 -9.271,4.064; OUT-.1 9.271,6.604; OUT-.2 9.271,4.064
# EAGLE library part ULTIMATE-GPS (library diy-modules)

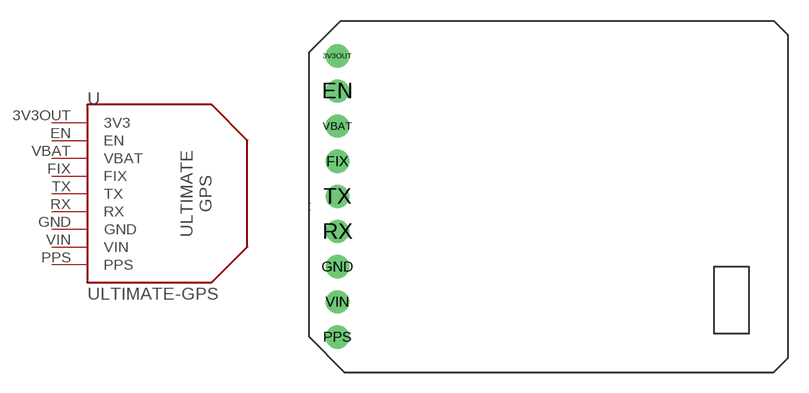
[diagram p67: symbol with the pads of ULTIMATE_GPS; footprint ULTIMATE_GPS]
Designator prefix -

## ULTIMATE-GPS  [ULTIMATE_GPS]
3V3OUT  3V3  out
EN  EN  in
FIX  FIX  out
GND  GND  pwr
PPS  PPS  out
RX  RX  in
TX  TX  out
VBAT  VBAT
VIN  VIN  pwr

## Footprint ULTIMATE_GPS (pad centres in mm)
drill 1 pad 1.676: 3V3OUT 0,10.16; EN 0,7.62; FIX 0,2.54; GND 0,-5.08; PPS 0,-10.16; RX 0,-2.54; TX 0,0; VBAT 0,5.08; VIN 0,-7.62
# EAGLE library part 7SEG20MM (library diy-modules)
7 Segment Display, 20mm digits

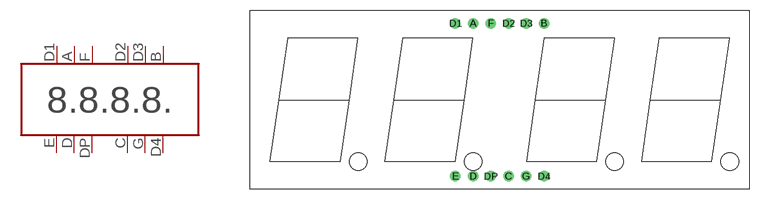
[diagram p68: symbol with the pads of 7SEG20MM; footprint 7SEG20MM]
Designator prefix LED

## 7SEG20MM  [7SEG20MM]
A  A
B  B
C  C
D  D
D1  D1
D2  D2
D3  D3
D4  D4
DP  DP
E  E
F  F
G  G

## Footprint 7SEG20MM (pad centres in mm)
drill 1: A -3.81,11; B 6.35,11; C 1.27,-11; D -3.81,-11; D1 -6.35,11; D2 1.27,11; D3 3.81,11; D4 6.35,-11; DP -1.27,-11; E -6.35,-11; F -1.27,11; G 3.81,-11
